One B-rep face of a CAD part: STEP entity #1341.
In plain terms, the cylindrical face has radius 33 mm (diameter 66 mm), a partial arc.
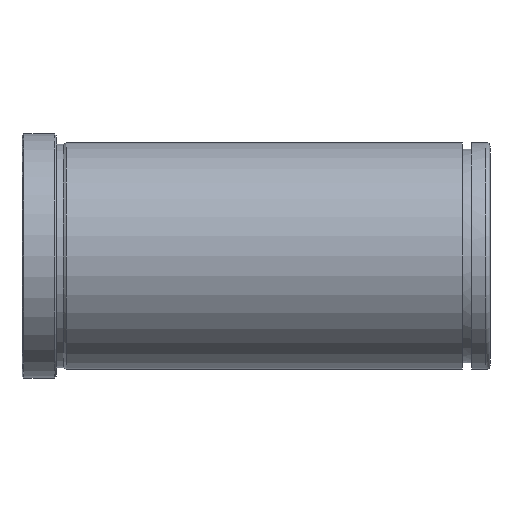
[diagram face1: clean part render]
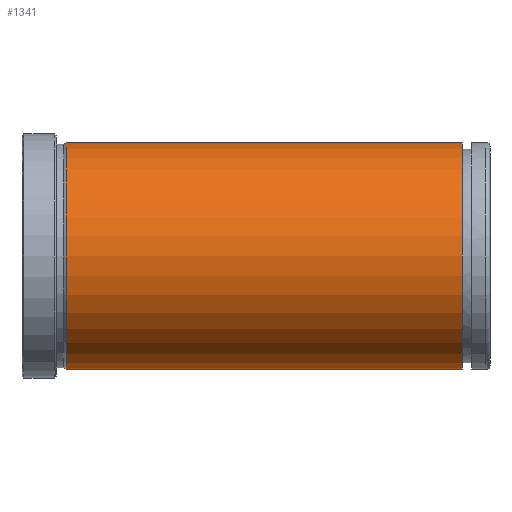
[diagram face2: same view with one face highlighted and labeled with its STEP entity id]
Its self-contained STEP definition (entity closure, numbers rounded to 3 decimals):
#1203=CARTESIAN_POINT('Vertex',(128.,0.,33.)) ;
#1206=CARTESIAN_POINT('Axis2P3D Location',(128.,0.,0.)) ;
#1210=CARTESIAN_POINT('Vertex',(128.,-33.,0.)) ;
#1213=CARTESIAN_POINT('Axis2P3D Location',(128.,0.,0.)) ;
#1217=CARTESIAN_POINT('Vertex',(128.,0.,-33.)) ;
#1247=CARTESIAN_POINT('Vertex',(12.866,0.,-33.)) ;
#1254=CARTESIAN_POINT('Vertex',(12.866,0.,33.)) ;
#1283=CARTESIAN_POINT('Axis2P3D Location',(12.866,0.,0.)) ;
#1287=CARTESIAN_POINT('Vertex',(12.866,-33.,0.)) ;
#1290=CARTESIAN_POINT('Axis2P3D Location',(12.866,0.,0.)) ;
#1309=CARTESIAN_POINT('Line Origine',(272.,0.,33.)) ;
#1314=CARTESIAN_POINT('Line Origine',(272.,0.,-33.)) ;
#1328=CARTESIAN_POINT('Axis2P3D Location',(272.,0.,0.)) ;
#1207=DIRECTION('Axis2P3D Direction',(1.,0.,-0.)) ;
#1214=DIRECTION('Axis2P3D Direction',(1.,0.,-0.)) ;
#1284=DIRECTION('Axis2P3D Direction',(1.,0.,-0.)) ;
#1291=DIRECTION('Axis2P3D Direction',(1.,0.,-0.)) ;
#1310=DIRECTION('Vector Direction',(-1.,0.,0.)) ;
#1315=DIRECTION('Vector Direction',(-1.,0.,0.)) ;
#1329=DIRECTION('Axis2P3D Direction',(-1.,-0.,-0.)) ;
#1330=DIRECTION('Axis2P3D XDirection',(0.,0.,-1.)) ;
#1208=AXIS2_PLACEMENT_3D('Circle Axis2P3D',#1206,#1207,$) ;
#1215=AXIS2_PLACEMENT_3D('Circle Axis2P3D',#1213,#1214,$) ;
#1285=AXIS2_PLACEMENT_3D('Circle Axis2P3D',#1283,#1284,$) ;
#1292=AXIS2_PLACEMENT_3D('Circle Axis2P3D',#1290,#1291,$) ;
#1331=AXIS2_PLACEMENT_3D('Cylinder Axis2P3D',#1328,#1329,#1330) ;
#1334=ORIENTED_EDGE('',*,*,#1318,.T.) ;
#1335=ORIENTED_EDGE('',*,*,#1219,.F.) ;
#1336=ORIENTED_EDGE('',*,*,#1212,.F.) ;
#1337=ORIENTED_EDGE('',*,*,#1313,.T.) ;
#1338=ORIENTED_EDGE('',*,*,#1294,.T.) ;
#1339=ORIENTED_EDGE('',*,*,#1289,.T.) ;
#1311=VECTOR('Line Direction',#1310,1.) ;
#1316=VECTOR('Line Direction',#1315,1.) ;
#1341=ADVANCED_FACE('553-50X136',(#1340),#1332,.T.) ;
#1209=CIRCLE('generated circle',#1208,33.) ;
#1216=CIRCLE('generated circle',#1215,33.) ;
#1286=CIRCLE('generated circle',#1285,33.) ;
#1293=CIRCLE('generated circle',#1292,33.) ;
#1332=CYLINDRICAL_SURFACE('generated cylinder',#1331,33.) ;
#1212=EDGE_CURVE('',#1204,#1211,#1209,.T.) ;
#1219=EDGE_CURVE('',#1211,#1218,#1216,.T.) ;
#1289=EDGE_CURVE('',#1288,#1248,#1286,.T.) ;
#1294=EDGE_CURVE('',#1255,#1288,#1293,.T.) ;
#1313=EDGE_CURVE('',#1204,#1255,#1312,.T.) ;
#1318=EDGE_CURVE('',#1248,#1218,#1317,.F.) ;
#1333=EDGE_LOOP('',(#1334,#1335,#1336,#1337,#1338,#1339)) ;
#1340=FACE_OUTER_BOUND('',#1333,.T.) ;
#1312=LINE('Line',#1309,#1311) ;
#1317=LINE('Line',#1314,#1316) ;
#1204=VERTEX_POINT('',#1203) ;
#1211=VERTEX_POINT('',#1210) ;
#1218=VERTEX_POINT('',#1217) ;
#1248=VERTEX_POINT('',#1247) ;
#1255=VERTEX_POINT('',#1254) ;
#1288=VERTEX_POINT('',#1287) ;
